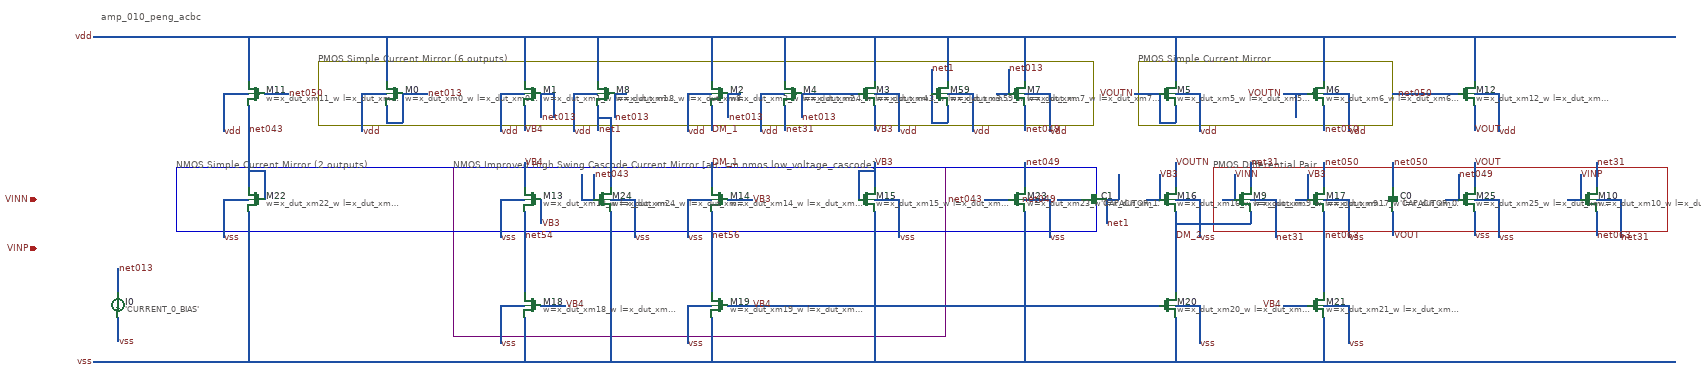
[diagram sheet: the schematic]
v {xschem version=3.4.6 file_version=1.2}
G {}
K {}
V {}
S {}
E {}
T {amp_010_peng_acbc} -1740 -200 0 0 0.4 0.4 {}
C {devices/capa_np.sym} 1435 260 0 0 {name=C0 value='CAPACITOR_0'}
C {devices/capa_np.sym} 700 260 1 0 {name=C1 value='CAPACITOR_1'}
C {devices/isource_np.sym} -1700 520 0 0 {name=I0 value='CURRENT_0_BIAS'}
C {devices/sg13_lv_pmos_np.sym} -1020 0 0 1 {name=M0 model=sg13_lv_pmos spiceprefix=X w=x_dut_xm0_w l=x_dut_xm0_l m=x_dut_xm0_m}
C {devices/sg13_lv_pmos_np.sym} -680 0 0 1 {name=M1 model=sg13_lv_pmos spiceprefix=X w=x_dut_xm1_w l=x_dut_xm1_l m=x_dut_xm1_m}
C {devices/sg13_lv_pmos_np.sym} 1915 260 0 0 {name=M10 model=sg13_lv_pmos spiceprefix=X w=x_dut_xm10_w l=x_dut_xm10_l m=x_dut_xm10_m}
C {devices/sg13_lv_pmos_np.sym} -1360 0 0 1 {name=M11 model=sg13_lv_pmos spiceprefix=X w=x_dut_xm11_w l=x_dut_xm11_l m=x_dut_xm11_m}
C {devices/sg13_lv_pmos_np.sym} 1615 0 0 0 {name=M12 model=sg13_lv_pmos spiceprefix=X w=x_dut_xm12_w l=x_dut_xm12_l m=x_dut_xm12_m}
C {devices/sg13_lv_nmos_np.sym} -680 260 0 1 {name=M13 model=sg13_lv_nmos spiceprefix=X w=x_dut_xm13_w l=x_dut_xm13_l m=x_dut_xm13_m}
C {devices/sg13_lv_nmos_np.sym} -220 260 0 1 {name=M14 model=sg13_lv_nmos spiceprefix=X w=x_dut_xm14_w l=x_dut_xm14_l m=x_dut_xm14_m}
C {devices/sg13_lv_nmos_np.sym} 140 260 0 0 {name=M15 model=sg13_lv_nmos spiceprefix=X w=x_dut_xm15_w l=x_dut_xm15_l m=x_dut_xm15_m}
C {devices/sg13_lv_nmos_np.sym} 880 260 0 0 {name=M16 model=sg13_lv_nmos spiceprefix=X w=x_dut_xm16_w l=x_dut_xm16_l m=x_dut_xm16_m}
C {devices/sg13_lv_nmos_np.sym} 1245 260 0 0 {name=M17 model=sg13_lv_nmos spiceprefix=X w=x_dut_xm17_w l=x_dut_xm17_l m=x_dut_xm17_m}
C {devices/sg13_lv_nmos_np.sym} -680 520 0 1 {name=M18 model=sg13_lv_nmos spiceprefix=X w=x_dut_xm18_w l=x_dut_xm18_l m=x_dut_xm18_m}
C {devices/sg13_lv_nmos_np.sym} -220 520 0 1 {name=M19 model=sg13_lv_nmos spiceprefix=X w=x_dut_xm19_w l=x_dut_xm19_l m=x_dut_xm19_m}
C {devices/sg13_lv_pmos_np.sym} -220 0 0 1 {name=M2 model=sg13_lv_pmos spiceprefix=X w=x_dut_xm2_w l=x_dut_xm2_l m=x_dut_xm2_m}
C {devices/sg13_lv_nmos_np.sym} 880 520 0 0 {name=M20 model=sg13_lv_nmos spiceprefix=X w=x_dut_xm20_w l=x_dut_xm20_l m=x_dut_xm20_m}
C {devices/sg13_lv_nmos_np.sym} 1245 520 0 0 {name=M21 model=sg13_lv_nmos spiceprefix=X w=x_dut_xm21_w l=x_dut_xm21_l m=x_dut_xm21_m}
C {devices/sg13_lv_nmos_np.sym} -1360 260 0 1 {name=M22 model=sg13_lv_nmos spiceprefix=X w=x_dut_xm22_w l=x_dut_xm22_l m=x_dut_xm22_m}
C {devices/sg13_lv_nmos_np.sym} 510 260 0 0 {name=M23 model=sg13_lv_nmos spiceprefix=X w=x_dut_xm23_w l=x_dut_xm23_l m=x_dut_xm23_m}
C {devices/sg13_lv_nmos_np.sym} -510 260 0 0 {name=M24 model=sg13_lv_nmos spiceprefix=X w=x_dut_xm24_w l=x_dut_xm24_l m=x_dut_xm24_m}
C {devices/sg13_lv_nmos_np.sym} 1615 260 0 0 {name=M25 model=sg13_lv_nmos spiceprefix=X w=x_dut_xm25_w l=x_dut_xm25_l m=x_dut_xm25_m}
C {devices/sg13_lv_pmos_np.sym} 140 0 0 0 {name=M3 model=sg13_lv_pmos spiceprefix=X w=x_dut_xm3_w l=x_dut_xm3_l m=x_dut_xm3_m}
C {devices/sg13_lv_pmos_np.sym} -40 0 0 1 {name=M4 model=sg13_lv_pmos spiceprefix=X w=x_dut_xm4_w l=x_dut_xm4_l m=x_dut_xm4_m}
C {devices/sg13_lv_pmos_np.sym} 880 0 0 0 {name=M5 model=sg13_lv_pmos spiceprefix=X w=x_dut_xm5_w l=x_dut_xm5_l m=x_dut_xm5_m}
C {devices/sg13_lv_pmos_np.sym} 320 0 0 0 {name=M59 model=sg13_lv_pmos spiceprefix=X w=x_dut_xm59_w l=x_dut_xm59_l m=x_dut_xm59_m}
C {devices/sg13_lv_pmos_np.sym} 1245 0 0 0 {name=M6 model=sg13_lv_pmos spiceprefix=X w=x_dut_xm6_w l=x_dut_xm6_l m=x_dut_xm6_m}
C {devices/sg13_lv_pmos_np.sym} 510 0 0 0 {name=M7 model=sg13_lv_pmos spiceprefix=X w=x_dut_xm7_w l=x_dut_xm7_l m=x_dut_xm7_m}
C {devices/sg13_lv_pmos_np.sym} -500 0 0 1 {name=M8 model=sg13_lv_pmos spiceprefix=X w=x_dut_xm8_w l=x_dut_xm8_l m=x_dut_xm8_m}
C {devices/sg13_lv_pmos_np.sym} 1065 260 0 0 {name=M9 model=sg13_lv_pmos spiceprefix=X w=x_dut_xm9_w l=x_dut_xm9_l m=x_dut_xm9_m}
N -1700 430 -1700 490 {}
N -1700 550 -1700 610 {}
N -1440 0 -1440 94 {}
N -1440 260 -1440 354 {}
N -1380 -140 -1380 -30 {}
N -1380 30 -1380 230 {}
N -1380 290 -1380 660 {}
N -1340 190 -1340 260 {}
N -1100 0 -1100 94 {}
N -1040 -140 -1040 -30 {}
N -1040 30 -1040 70 {}
N -1000 0 -1000 70 {}
N -760 0 -760 94 {}
N -760 260 -760 354 {}
N -760 520 -760 614 {}
N -700 -140 -700 -30 {}
N -700 30 -700 90 {}
N -700 170 -700 230 {}
N -700 290 -700 490 {}
N -700 550 -700 660 {}
N -660 0 -660 60 {}
N -660 260 -660 320 {}
N -630 0 -630 60 {}
N -580 0 -580 94 {}
N -560 200 -560 260 {}
N -530 200 -530 260 {}
N -520 -140 -520 -30 {}
N -520 30 -520 90 {}
N -490 60 -490 230 {}
N -490 290 -490 660 {}
N -480 0 -480 60 {}
N -430 260 -430 354 {}
N -300 0 -300 94 {}
N -300 260 -300 354 {}
N -300 520 -300 614 {}
N -240 -140 -240 -30 {}
N -240 30 -240 90 {}
N -240 170 -240 230 {}
N -240 290 -240 490 {}
N -240 550 -240 660 {}
N -200 0 -200 60 {}
N -120 0 -120 94 {}
N -60 -140 -60 -30 {}
N -60 30 -60 90 {}
N -20 0 -20 60 {}
N 120 190 120 260 {}
N 160 -140 160 -30 {}
N 160 30 160 90 {}
N 160 170 160 230 {}
N 160 290 160 660 {}
N 220 0 220 94 {}
N 220 260 220 354 {}
N 300 -60 300 70 {}
N 340 -140 340 -30 {}
N 340 30 340 70 {}
N 400 0 400 94 {}
N 490 -60 490 0 {}
N 530 -140 530 -30 {}
N 530 30 530 90 {}
N 530 170 530 230 {}
N 530 290 530 660 {}
N 590 0 590 94 {}
N 590 260 590 354 {}
N 730 260 730 320 {}
N 760 200 760 260 {}
N 860 0 860 70 {}
N 860 200 860 260 {}
N 900 -140 900 -30 {}
N 900 30 900 70 {}
N 900 170 900 230 {}
N 900 290 900 490 {}
N 900 550 900 660 {}
N 960 0 960 94 {}
N 960 260 960 354 {}
N 960 520 960 614 {}
N 1045 200 1045 260 {}
N 1085 170 1085 230 {}
N 1085 290 1085 320 {}
N 1145 260 1145 354 {}
N 1195 0 1195 60 {}
N 1225 200 1225 260 {}
N 1265 -140 1265 -30 {}
N 1265 30 1265 90 {}
N 1265 170 1265 230 {}
N 1265 290 1265 490 {}
N 1265 550 1265 660 {}
N 1325 0 1325 94 {}
N 1325 260 1325 354 {}
N 1325 520 1325 614 {}
N 1435 170 1435 230 {}
N 1435 290 1435 350 {}
N 1595 200 1595 260 {}
N 1635 -140 1635 -30 {}
N 1635 30 1635 90 {}
N 1635 170 1635 230 {}
N 1635 290 1635 350 {}
N 1695 0 1695 94 {}
N 1695 260 1695 354 {}
N 1895 200 1895 260 {}
N 1935 170 1935 230 {}
N 1935 290 1935 350 {}
N 1995 260 1995 354 {}
N -1760 -140 2130 -140 {}
N -1440 0 -1380 0 {}
N -1340 0 -1280 0 {}
N -1100 0 -1040 0 {}
N -1000 0 -940 0 {}
N -760 0 -700 0 {}
N -660 0 -630 0 {}
N -580 0 -520 0 {}
N -480 0 -450 0 {}
N -300 0 -240 0 {}
N -200 0 -170 0 {}
N -120 0 -60 0 {}
N -20 0 120 0 {}
N 160 0 220 0 {}
N 340 0 400 0 {}
N 460 0 490 0 {}
N 530 0 590 0 {}
N 800 0 860 0 {}
N 900 0 960 0 {}
N 1165 0 1225 0 {}
N 1265 0 1325 0 {}
N 1435 0 1595 0 {}
N 1635 0 1695 0 {}
N -520 60 -490 60 {}
N -1040 70 -1000 70 {}
N 300 70 340 70 {}
N 860 70 900 70 {}
N -1380 190 -1340 190 {}
N 120 190 160 190 {}
N -1440 260 -1380 260 {}
N -760 260 -700 260 {}
N -560 260 -530 260 {}
N -490 260 -430 260 {}
N -300 260 -240 260 {}
N -200 260 -140 260 {}
N 160 260 220 260 {}
N 430 260 490 260 {}
N 530 260 590 260 {}
N 610 260 670 260 {}
N 730 260 760 260 {}
N 830 260 860 260 {}
N 900 260 960 260 {}
N 1015 260 1045 260 {}
N 1085 260 1145 260 {}
N 1195 260 1225 260 {}
N 1265 260 1325 260 {}
N 1565 260 1595 260 {}
N 1635 260 1695 260 {}
N 1865 260 1895 260 {}
N 1935 260 1995 260 {}
N 900 320 1085 320 {}
N -760 520 -700 520 {}
N -660 520 -600 520 {}
N -300 520 -240 520 {}
N -200 520 860 520 {}
N 900 520 960 520 {}
N 1165 520 1225 520 {}
N 1265 520 1325 520 {}
N -1760 660 2130 660 {}
C {devices/lab_wire.sym} -1760 -140 0 0 {name=l0 lab=vdd}
C {devices/lab_wire.sym} -1760 660 0 0 {name=l1 lab=vss}
C {devices/lab_wire.sym} -240 90 2 0 {name=l2 lab=DM_1}
C {devices/lab_wire.sym} -240 170 0 1 {name=l3 lab=DM_1}
C {devices/lab_wire.sym} 900 350 2 0 {name=l4 lab=DM_2}
C {devices/lab_wire.sym} -660 320 2 0 {name=l5 lab=VB3}
C {devices/lab_wire.sym} -140 260 0 1 {name=l6 lab=VB3}
C {devices/lab_wire.sym} 160 170 0 1 {name=l7 lab=VB3}
C {devices/lab_wire.sym} 160 90 2 0 {name=l8 lab=VB3}
C {devices/lab_wire.sym} 860 200 0 1 {name=l9 lab=VB3}
C {devices/lab_wire.sym} 1225 200 0 1 {name=l10 lab=VB3}
C {devices/lab_wire.sym} -700 90 2 0 {name=l11 lab=VB4}
C {devices/lab_wire.sym} -700 170 0 1 {name=l12 lab=VB4}
C {devices/lab_wire.sym} -600 520 0 1 {name=l13 lab=VB4}
C {devices/lab_wire.sym} -140 520 0 1 {name=l14 lab=VB4}
C {devices/lab_wire.sym} 1165 520 0 0 {name=l15 lab=VB4}
C {devices/lab_wire.sym} 1045 200 0 1 {name=l16 lab=VINN}
C {devices/lab_wire.sym} 1895 200 0 1 {name=l17 lab=VINP}
C {devices/lab_wire.sym} 1435 350 2 0 {name=l18 lab=VOUT}
C {devices/lab_wire.sym} 1635 90 2 0 {name=l19 lab=VOUT}
C {devices/lab_wire.sym} 1635 170 0 1 {name=l20 lab=VOUT}
C {devices/lab_wire.sym} 800 0 0 0 {name=l21 lab=VOUTN}
C {devices/lab_wire.sym} 900 170 0 1 {name=l22 lab=VOUTN}
C {devices/lab_wire.sym} 1165 0 0 0 {name=l23 lab=VOUTN}
C {devices/lab_wire.sym} -940 0 0 1 {name=l24 lab=net013}
C {devices/lab_wire.sym} -660 60 2 0 {name=l25 lab=net013}
C {devices/lab_wire.sym} -480 60 2 0 {name=l26 lab=net013}
C {devices/lab_wire.sym} -200 60 2 0 {name=l27 lab=net013}
C {devices/lab_wire.sym} -20 60 2 0 {name=l28 lab=net013}
C {devices/lab_wire.sym} 490 -60 0 1 {name=l29 lab=net013}
C {devices/lab_wire.sym} -1380 90 2 0 {name=l30 lab=net043}
C {devices/lab_wire.sym} -530 200 0 1 {name=l31 lab=net043}
C {devices/lab_wire.sym} 430 260 0 0 {name=l32 lab=net043}
C {devices/lab_wire.sym} 530 90 2 0 {name=l33 lab=net049}
C {devices/lab_wire.sym} 530 170 0 1 {name=l34 lab=net049}
C {devices/lab_wire.sym} 610 260 0 0 {name=l35 lab=net049}
C {devices/lab_wire.sym} 1595 200 0 1 {name=l36 lab=net049}
C {devices/lab_wire.sym} -1280 0 0 1 {name=l37 lab=net050}
C {devices/lab_wire.sym} 1265 90 2 0 {name=l38 lab=net050}
C {devices/lab_wire.sym} 1265 170 0 1 {name=l39 lab=net050}
C {devices/lab_wire.sym} 1435 170 0 1 {name=l40 lab=net050}
C {devices/lab_wire.sym} 1535 0 0 0 {name=l41 lab=net050}
C {devices/lab_wire.sym} 1265 350 2 0 {name=l42 lab=net063}
C {devices/lab_wire.sym} 1935 350 2 0 {name=l43 lab=net063}
C {devices/lab_wire.sym} -520 90 2 0 {name=l44 lab=net1}
C {devices/lab_wire.sym} 300 -60 0 1 {name=l45 lab=net1}
C {devices/lab_wire.sym} 730 320 2 0 {name=l46 lab=net1}
C {devices/lab_wire.sym} -60 90 2 0 {name=l47 lab=net31}
C {devices/lab_wire.sym} 1085 170 0 1 {name=l48 lab=net31}
C {devices/lab_wire.sym} 1935 170 0 1 {name=l49 lab=net31}
C {devices/lab_wire.sym} -700 350 2 0 {name=l50 lab=net54}
C {devices/lab_wire.sym} -240 350 2 0 {name=l51 lab=net56}
C {devices/lab_wire.sym} 1995 354 2 0 {name=l52 lab=net31}
C {devices/lab_wire.sym} 1145 354 2 0 {name=l53 lab=net31}
C {devices/lab_wire.sym} -1100 94 2 0 {name=l54 lab=vdd}
C {devices/lab_wire.sym} -760 94 2 0 {name=l55 lab=vdd}
C {devices/lab_wire.sym} -1440 94 2 0 {name=l56 lab=vdd}
C {devices/lab_wire.sym} 1695 94 2 0 {name=l57 lab=vdd}
C {devices/lab_wire.sym} -300 94 2 0 {name=l58 lab=vdd}
C {devices/lab_wire.sym} 220 94 2 0 {name=l59 lab=vdd}
C {devices/lab_wire.sym} -120 94 2 0 {name=l60 lab=vdd}
C {devices/lab_wire.sym} 960 94 2 0 {name=l61 lab=vdd}
C {devices/lab_wire.sym} 400 94 2 0 {name=l62 lab=vdd}
C {devices/lab_wire.sym} 1325 94 2 0 {name=l63 lab=vdd}
C {devices/lab_wire.sym} 590 94 2 0 {name=l64 lab=vdd}
C {devices/lab_wire.sym} -580 94 2 0 {name=l65 lab=vdd}
C {devices/lab_wire.sym} -760 354 2 0 {name=l66 lab=vss}
C {devices/lab_wire.sym} -300 354 2 0 {name=l67 lab=vss}
C {devices/lab_wire.sym} 220 354 2 0 {name=l68 lab=vss}
C {devices/lab_wire.sym} 960 354 2 0 {name=l69 lab=vss}
C {devices/lab_wire.sym} 1325 354 2 0 {name=l70 lab=vss}
C {devices/lab_wire.sym} -760 614 2 0 {name=l71 lab=vss}
C {devices/lab_wire.sym} -300 614 2 0 {name=l72 lab=vss}
C {devices/lab_wire.sym} 960 614 2 0 {name=l73 lab=vss}
C {devices/lab_wire.sym} 1325 614 2 0 {name=l74 lab=vss}
C {devices/lab_wire.sym} -1440 354 2 0 {name=l75 lab=vss}
C {devices/lab_wire.sym} 590 354 2 0 {name=l76 lab=vss}
C {devices/lab_wire.sym} -430 354 2 0 {name=l77 lab=vss}
C {devices/lab_wire.sym} 1695 354 2 0 {name=l78 lab=vss}
C {devices/lab_wire.sym} -1700 430 0 1 {name=l79 lab=net013}
C {devices/lab_wire.sym} -1700 610 2 0 {name=l80 lab=vss}
C {devices/lab_wire.sym} 1635 350 2 0 {name=l81 lab=vss}
C {devices/ipin.sym} -1900 260 0 0 {name=p0 lab=VINN}
C {devices/ipin.sym} -1900 380 0 0 {name=p1 lab=VINP}
B 8 -1208 -78 698 78 {fill=0}
T {PMOS Simple Current Mirror (6 outputs)} -1208 -96 0 0 0.3 0.3 {layer=8}
B 10 -876 182 336 598 {fill=0}
T {NMOS Improved High Swing Cascode Current Mirror [alt: cm.nmos.low_voltage_cascode]} -876 164 0 0 0.3 0.3 {layer=10}
B 12 -1556 182 706 338 {fill=0}
T {NMOS Simple Current Mirror (2 outputs)} -1556 164 0 0 0.3 0.3 {layer=12}
B 21 810 -78 1433 78 {fill=0}
T {PMOS Simple Current Mirror} 810 -96 0 0 0.3 0.3 {layer=21}
B 15 995 182 2111 338 {fill=0}
T {PMOS Differential Pair} 995 164 0 0 0.3 0.3 {layer=15}
